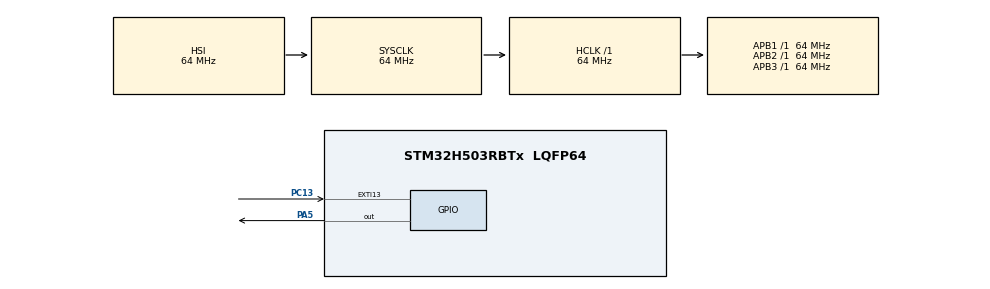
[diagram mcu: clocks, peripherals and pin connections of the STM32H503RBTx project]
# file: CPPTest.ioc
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BOOTPATH.BootPathName=LEGACY
BOOTPATH.UserSelectedBootPath=LEGACY
Mcu.Family=STM32H5
Mcu.Name=STM32H503RBTx
Mcu.Package=LQFP64
NUCLEO-H503RB.BUTTON=1
NUCLEO-H503RB.Bsp_Common_DEMO=true
NUCLEO-H503RB.LD2=true
NUCLEO-H503RB.VCP=true
NVIC.EXTI13_IRQn=true\:0\:0\:false\:false\:true\:false\:true\:true
NVIC.PriorityGroup=NVIC_PRIORITYGROUP_4
PA3.Signal=USART3_RX
PA4.Signal=USART3_TX
PA5.Signal=GPIO_Output
PB3(JTDO/TRACESWO).Signal=S_TIM2_CH2
PC13.Signal=GPXTI13
ProjectManager.HeapSize=0x200
ProjectManager.StackSize=0x400
ProjectManager.TargetToolchain=CMake
RCC.ADCFreq_Value=64000000
RCC.AHBFreq_Value=64000000
RCC.APB1Freq_Value=64000000
RCC.APB1TimFreq_Value=64000000
RCC.APB2Freq_Value=64000000
RCC.APB2TimFreq_Value=64000000
RCC.APB3Freq_Value=64000000
RCC.CSI_VALUE=4000000
RCC.CortexFreq_Value=64000000
RCC.EPOD_VALUE=4000000
RCC.HCLKFreq_Value=64000000
RCC.HSE_VALUE=24000000
RCC.HSI48_VALUE=48000000
RCC.HSIDiv=RCC_HSI_DIV1
RCC.HSI_VALUE=64000000
RCC.LSE_VALUE=32768
RCC.LSIRC_VALUE=32000
RCC.PLLN=32
RCC.SYSCLKFreq_VALUE=64000000
RCC.USBFreq_Value=48000000
RCC.VCOOutputFreq_Value=128000000
SH.S_TIM2_CH2.0=TIM2_CH2
TIM2.PeriodNoDither=4294967295
TIM2.Prescaler=63
VP_BOOTPATH_VS_BOOTPATH.Mode=BP_Activate
VP_CORTEX_M33_NS_VS_Hclk.Mode=Hclk_Mode
VP_ICACHE_VS_ICACHE.Mode=DirectMappedCache
VP_MEMORYMAP_VS_MEMORYMAP.Mode=CurAppReg
VP_NUCLEO-H503RB_VS_BSP_COMMON.Mode=COMMON
VP_PWR_VS_DBSignals.Mode=DisableDeadBatterySignals
VP_PWR_VS_LPOM.Mode=PowerOptimisation
VP_PWR_VS_SECSignals.Mode=Security/Privilege
VP_TIM2_VS_ClockSourceINT.Mode=Internal
board=NUCLEO-H503RB

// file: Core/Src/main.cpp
/* USER CODE BEGIN Header */
/**
 ******************************************************************************
 * @file           : main.cpp
 * @brief          : Main program body
 ******************************************************************************
 * @attention
 *
 * Copyright (c) 2025 STMicroelectronics.
 * All rights reserved.
 *
 * This software is licensed under terms that can be found in the LICENSE file
 * in the root directory of this software component.
 * If no LICENSE file comes with this software, it is provided AS-IS.
 *
 ******************************************************************************
 */
/* USER CODE END Header */
#include "main.h"

COM_InitTypeDef BspCOMInit;
__IO uint32_t BspButtonState = BUTTON_RELEASED;

TIM_HandleTypeDef htim2;

void SystemClock_Config(void);
static void MX_GPIO_Init(void);
static void MX_TIM2_Init(void);
static void MX_ICACHE_Init(void);
uint32_t micros(void);

int main(void)
{
  HAL_Init();
  SystemClock_Config();
  MX_GPIO_Init();
  MX_TIM2_Init();

  uint32_t deltaX, deltaY, deltaA, deltaB, currentPosA, currentPosB;
  deltaX = 1000 * 8;
  deltaY = 500 * 8;
  deltaA = deltaX + deltaY;
  deltaB = deltaX - deltaY;
  currentPosA = 0;
  currentPosB = 0;

  uint32_t previousTimeA = micros(); // Store last time event
  uint32_t previousTimeB = micros();
  bool ledStateA = false; // Track LED state
  bool ledStateB = false; // Track LED state

  while (1)
  {
    uint32_t currentTime = micros();

    // Motor A
    // Keep running until finished
    if (currentPosA < deltaA)
    {
      if (ledStateA && (currentTime - previousTimeA >= 2))
      {                                                       // If ON for some time (microseconds)
        HAL_GPIO_WritePin(GPIOB, GPIO_PIN_5, GPIO_PIN_RESET); // Turn off
        previousTimeA = currentTime;
        ledStateA = false;
      }
      else if (!ledStateA && (currentTime - previousTimeA >= 166))
      {                                                     // If OFF for some time (microseconds)
        HAL_GPIO_WritePin(GPIOB, GPIO_PIN_5, GPIO_PIN_SET); // Turn on (make a step)
        previousTimeA = currentTime;
        ledStateA = true;
        currentPosA++;
      }
    }

    // Motor B
    if (currentPosB < deltaB)
    {
      if (ledStateB && (currentTime - previousTimeB >= 2))
      {                                                       // If ON for some time (microseconds)
        HAL_GPIO_WritePin(GPIOB, GPIO_PIN_4, GPIO_PIN_RESET); // Turn off
        previousTimeB = currentTime;
        ledStateB = false;
      }
      else if (!ledStateB && (currentTime - previousTimeB >= 500))
      {                                                     // If OFF for some time (microseconds)
        HAL_GPIO_WritePin(GPIOB, GPIO_PIN_4, GPIO_PIN_SET); // Turn on (make a step)
        previousTimeB = currentTime;
        ledStateB = true;
        currentPosB++;
      }
    }
  }
}

uint32_t micros(void)
{
  return __HAL_TIM_GET_COUNTER(&htim2);
}

void SystemClock_Config(void)
{
  RCC_OscInitTypeDef RCC_OscInitStruct = {0};
  RCC_ClkInitTypeDef RCC_ClkInitStruct = {0};

  /** Configure the main internal regulator output voltage
   */
  __HAL_PWR_VOLTAGESCALING_CONFIG(PWR_REGULATOR_VOLTAGE_SCALE3);

  while (!__HAL_PWR_GET_FLAG(PWR_FLAG_VOSRDY))
  {
  }

  /** Initializes the RCC Oscillators according to the specified parameters
   * in the RCC_OscInitTypeDef structure.
   */
  RCC_OscInitStruct.OscillatorType = RCC_OSCILLATORTYPE_HSI;
  RCC_OscInitStruct.HSIState = RCC_HSI_ON;
  RCC_OscInitStruct.HSIDiv = RCC_HSI_DIV1;
  RCC_OscInitStruct.HSICalibrationValue = RCC_HSICALIBRATION_DEFAULT;
  RCC_OscInitStruct.PLL.PLLState = RCC_PLL_NONE;
  if (HAL_RCC_OscConfig(&RCC_OscInitStruct) != HAL_OK)
  {
    Error_Handler();
  }

  /** Initializes the CPU, AHB and APB buses clocks
   */
  RCC_ClkInitStruct.ClockType = RCC_CLOCKTYPE_HCLK | RCC_CLOCKTYPE_SYSCLK | RCC_CLOCKTYPE_PCLK1 | RCC_CLOCKTYPE_PCLK2 | RCC_CLOCKTYPE_PCLK3;
  RCC_ClkInitStruct.SYSCLKSource = RCC_SYSCLKSOURCE_HSI;
  RCC_ClkInitStruct.AHBCLKDivider = RCC_SYSCLK_DIV1;
  RCC_ClkInitStruct.APB1CLKDivider = RCC_HCLK_DIV1;
  RCC_ClkInitStruct.APB2CLKDivider = RCC_HCLK_DIV1;
  RCC_ClkInitStruct.APB3CLKDivider = RCC_HCLK_DIV1;

  if (HAL_RCC_ClockConfig(&RCC_ClkInitStruct, FLASH_LATENCY_3) != HAL_OK)
  {
    Error_Handler();
  }

  /** Configure the programming delay
   */
  __HAL_FLASH_SET_PROGRAM_DELAY(FLASH_PROGRAMMING_DELAY_1);
}

static void MX_ICACHE_Init(void)
{

  /** Enable instruction cache in 1-way (direct mapped cache)
   */
  if (HAL_ICACHE_ConfigAssociativityMode(ICACHE_1WAY) != HAL_OK)
  {
    Error_Handler();
  }
  if (HAL_ICACHE_Enable() != HAL_OK)
  {
    Error_Handler();
  }
}

static void MX_TIM2_Init(void)
{

  TIM_ClockConfigTypeDef sClockSourceConfig = {0};
  TIM_MasterConfigTypeDef sMasterConfig = {0};

  htim2.Instance = TIM2;
  htim2.Init.Prescaler = 63;
  htim2.Init.CounterMode = TIM_COUNTERMODE_UP;
  htim2.Init.Period = 4294967295;
  htim2.Init.ClockDivision = TIM_CLOCKDIVISION_DIV1;
  htim2.Init.AutoReloadPreload = TIM_AUTORELOAD_PRELOAD_DISABLE;
  if (HAL_TIM_Base_Init(&htim2) != HAL_OK)
  {
    Error_Handler();
  }
  sClockSourceConfig.ClockSource = TIM_CLOCKSOURCE_INTERNAL;
  if (HAL_TIM_ConfigClockSource(&htim2, &sClockSourceConfig) != HAL_OK)
  {
    Error_Handler();
  }
  sMasterConfig.MasterOutputTrigger = TIM_TRGO_RESET;
  sMasterConfig.MasterSlaveMode = TIM_MASTERSLAVEMODE_DISABLE;
  if (HAL_TIMEx_MasterConfigSynchronization(&htim2, &sMasterConfig) != HAL_OK)
  {
    Error_Handler();
  }
  /* USER CODE BEGIN TIM2_Init 2 */
  HAL_TIM_Base_Start(&htim2);
  /* USER CODE END TIM2_Init 2 */
}

// GPIO Initialization - all pins need to be initstruct here
static void MX_GPIO_Init(void)
{
  __HAL_RCC_GPIOB_CLK_ENABLE();
  GPIO_InitTypeDef GPIO_InitStruct = {0};
  GPIO_InitStruct.Pin = GPIO_PIN_4 | GPIO_PIN_5;
  GPIO_InitStruct.Mode = GPIO_MODE_OUTPUT_PP;
  GPIO_InitStruct.Pull = GPIO_NOPULL;
  GPIO_InitStruct.Speed = GPIO_SPEED_FREQ_LOW;
  HAL_GPIO_Init(GPIOB, &GPIO_InitStruct);
}

/**
 * @brief BSP Push Button callback
 * @param Button Specifies the pressed button
 * @retval None
 */
void BSP_PB_Callback(Button_TypeDef Button)
{
  if (Button == BUTTON_USER)
  {
    BspButtonState = BUTTON_PRESSED;
  }
}

void Error_Handler(void)
{
  __disable_irq();
  while (1)
  {
  }
}
